# OpenTallas memory compiler (tools/mem_compiler), ASAP7 abstract view
VERSION 5.7 ;
BUSBITCHARS "[]" ;
DIVIDERCHAR "/" ;
PROPERTYDEFINITIONS
  MACRO width INTEGER ;
  MACRO depth INTEGER ;
  MACRO banks INTEGER ;
END PROPERTYDEFINITIONS
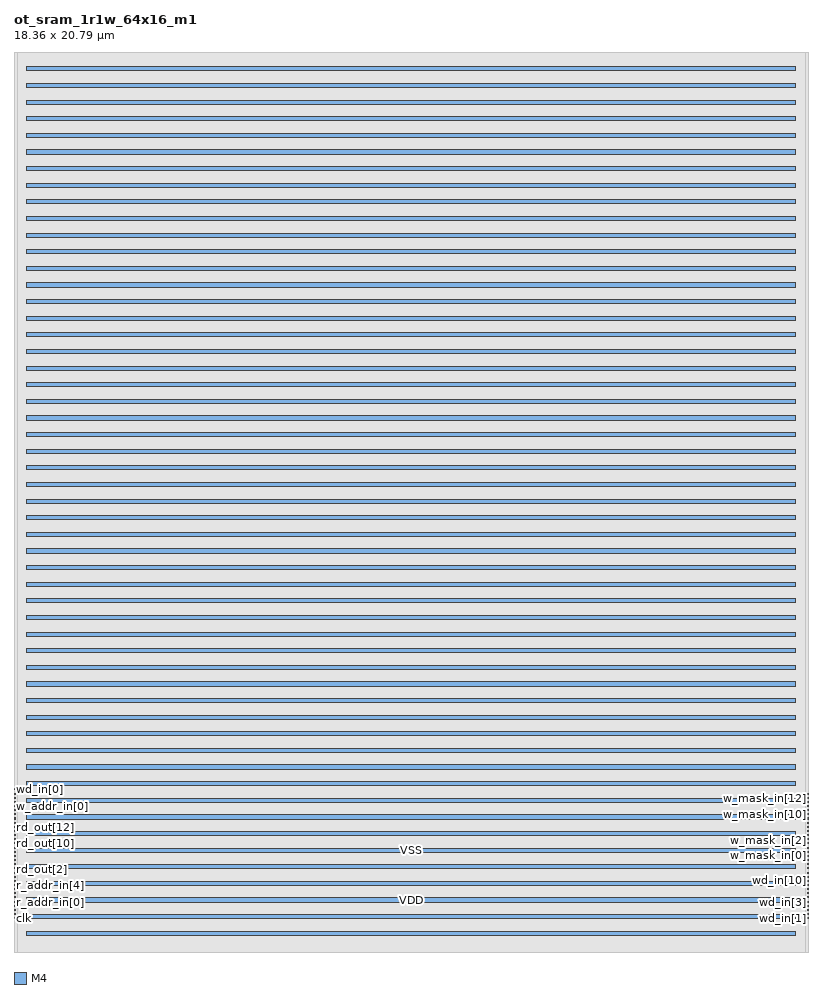
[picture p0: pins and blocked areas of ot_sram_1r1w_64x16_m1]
MACRO ot_sram_1r1w_64x16_m1
  PROPERTY width 16 ;
  PROPERTY depth 64 ;
  PROPERTY banks 1 ;
  FOREIGN ot_sram_1r1w_64x16_m1 0 0 ;
  SYMMETRY X Y R90 ;
  SIZE 18.360 BY 20.790 ;
  CLASS BLOCK ;
  PIN clk
    DIRECTION INPUT ;
    USE CLOCK ;
    SHAPE ABUTMENT ;
    PORT
      LAYER M4 ;
      RECT 0.000 0.768 0.024 0.792 ;
    END
  END clk
  PIN r_ce_in
    DIRECTION INPUT ;
    USE SIGNAL ;
    SHAPE ABUTMENT ;
    PORT
      LAYER M4 ;
      RECT 0.000 0.864 0.024 0.888 ;
    END
  END r_ce_in
  PIN r_addr_in[0]
    DIRECTION INPUT ;
    USE SIGNAL ;
    SHAPE ABUTMENT ;
    PORT
      LAYER M4 ;
      RECT 0.000 0.960 0.024 0.984 ;
    END
  END r_addr_in[0]
  PIN r_addr_in[1]
    DIRECTION INPUT ;
    USE SIGNAL ;
    SHAPE ABUTMENT ;
    PORT
      LAYER M4 ;
      RECT 0.000 1.056 0.024 1.080 ;
    END
  END r_addr_in[1]
  PIN r_addr_in[2]
    DIRECTION INPUT ;
    USE SIGNAL ;
    SHAPE ABUTMENT ;
    PORT
      LAYER M4 ;
      RECT 0.000 1.152 0.024 1.176 ;
    END
  END r_addr_in[2]
  PIN r_addr_in[3]
    DIRECTION INPUT ;
    USE SIGNAL ;
    SHAPE ABUTMENT ;
    PORT
      LAYER M4 ;
      RECT 0.000 1.248 0.024 1.272 ;
    END
  END r_addr_in[3]
  PIN r_addr_in[4]
    DIRECTION INPUT ;
    USE SIGNAL ;
    SHAPE ABUTMENT ;
    PORT
      LAYER M4 ;
      RECT 0.000 1.344 0.024 1.368 ;
    END
  END r_addr_in[4]
  PIN r_addr_in[5]
    DIRECTION INPUT ;
    USE SIGNAL ;
    SHAPE ABUTMENT ;
    PORT
      LAYER M4 ;
      RECT 0.000 1.440 0.024 1.464 ;
    END
  END r_addr_in[5]
  PIN rd_out[0]
    DIRECTION OUTPUT ;
    USE SIGNAL ;
    SHAPE ABUTMENT ;
    PORT
      LAYER M4 ;
      RECT 0.000 1.536 0.024 1.560 ;
    END
  END rd_out[0]
  PIN rd_out[1]
    DIRECTION OUTPUT ;
    USE SIGNAL ;
    SHAPE ABUTMENT ;
    PORT
      LAYER M4 ;
      RECT 0.000 1.632 0.024 1.656 ;
    END
  END rd_out[1]
  PIN rd_out[2]
    DIRECTION OUTPUT ;
    USE SIGNAL ;
    SHAPE ABUTMENT ;
    PORT
      LAYER M4 ;
      RECT 0.000 1.728 0.024 1.752 ;
    END
  END rd_out[2]
  PIN rd_out[3]
    DIRECTION OUTPUT ;
    USE SIGNAL ;
    SHAPE ABUTMENT ;
    PORT
      LAYER M4 ;
      RECT 0.000 1.824 0.024 1.848 ;
    END
  END rd_out[3]
  PIN rd_out[4]
    DIRECTION OUTPUT ;
    USE SIGNAL ;
    SHAPE ABUTMENT ;
    PORT
      LAYER M4 ;
      RECT 0.000 1.920 0.024 1.944 ;
    END
  END rd_out[4]
  PIN rd_out[5]
    DIRECTION OUTPUT ;
    USE SIGNAL ;
    SHAPE ABUTMENT ;
    PORT
      LAYER M4 ;
      RECT 0.000 2.016 0.024 2.040 ;
    END
  END rd_out[5]
  PIN rd_out[6]
    DIRECTION OUTPUT ;
    USE SIGNAL ;
    SHAPE ABUTMENT ;
    PORT
      LAYER M4 ;
      RECT 0.000 2.112 0.024 2.136 ;
    END
  END rd_out[6]
  PIN rd_out[7]
    DIRECTION OUTPUT ;
    USE SIGNAL ;
    SHAPE ABUTMENT ;
    PORT
      LAYER M4 ;
      RECT 0.000 2.208 0.024 2.232 ;
    END
  END rd_out[7]
  PIN rd_out[8]
    DIRECTION OUTPUT ;
    USE SIGNAL ;
    SHAPE ABUTMENT ;
    PORT
      LAYER M4 ;
      RECT 0.000 2.304 0.024 2.328 ;
    END
  END rd_out[8]
  PIN rd_out[9]
    DIRECTION OUTPUT ;
    USE SIGNAL ;
    SHAPE ABUTMENT ;
    PORT
      LAYER M4 ;
      RECT 0.000 2.400 0.024 2.424 ;
    END
  END rd_out[9]
  PIN rd_out[10]
    DIRECTION OUTPUT ;
    USE SIGNAL ;
    SHAPE ABUTMENT ;
    PORT
      LAYER M4 ;
      RECT 0.000 2.496 0.024 2.520 ;
    END
  END rd_out[10]
  PIN rd_out[11]
    DIRECTION OUTPUT ;
    USE SIGNAL ;
    SHAPE ABUTMENT ;
    PORT
      LAYER M4 ;
      RECT 0.000 2.592 0.024 2.616 ;
    END
  END rd_out[11]
  PIN rd_out[12]
    DIRECTION OUTPUT ;
    USE SIGNAL ;
    SHAPE ABUTMENT ;
    PORT
      LAYER M4 ;
      RECT 0.000 2.688 0.024 2.712 ;
    END
  END rd_out[12]
  PIN rd_out[13]
    DIRECTION OUTPUT ;
    USE SIGNAL ;
    SHAPE ABUTMENT ;
    PORT
      LAYER M4 ;
      RECT 0.000 2.784 0.024 2.808 ;
    END
  END rd_out[13]
  PIN rd_out[14]
    DIRECTION OUTPUT ;
    USE SIGNAL ;
    SHAPE ABUTMENT ;
    PORT
      LAYER M4 ;
      RECT 0.000 2.880 0.024 2.904 ;
    END
  END rd_out[14]
  PIN rd_out[15]
    DIRECTION OUTPUT ;
    USE SIGNAL ;
    SHAPE ABUTMENT ;
    PORT
      LAYER M4 ;
      RECT 0.000 2.976 0.024 3.000 ;
    END
  END rd_out[15]
  PIN w_ce_in
    DIRECTION INPUT ;
    USE SIGNAL ;
    SHAPE ABUTMENT ;
    PORT
      LAYER M4 ;
      RECT 0.000 3.072 0.024 3.096 ;
    END
  END w_ce_in
  PIN w_addr_in[0]
    DIRECTION INPUT ;
    USE SIGNAL ;
    SHAPE ABUTMENT ;
    PORT
      LAYER M4 ;
      RECT 0.000 3.168 0.024 3.192 ;
    END
  END w_addr_in[0]
  PIN w_addr_in[1]
    DIRECTION INPUT ;
    USE SIGNAL ;
    SHAPE ABUTMENT ;
    PORT
      LAYER M4 ;
      RECT 0.000 3.264 0.024 3.288 ;
    END
  END w_addr_in[1]
  PIN w_addr_in[2]
    DIRECTION INPUT ;
    USE SIGNAL ;
    SHAPE ABUTMENT ;
    PORT
      LAYER M4 ;
      RECT 0.000 3.360 0.024 3.384 ;
    END
  END w_addr_in[2]
  PIN w_addr_in[3]
    DIRECTION INPUT ;
    USE SIGNAL ;
    SHAPE ABUTMENT ;
    PORT
      LAYER M4 ;
      RECT 0.000 3.456 0.024 3.480 ;
    END
  END w_addr_in[3]
  PIN w_addr_in[4]
    DIRECTION INPUT ;
    USE SIGNAL ;
    SHAPE ABUTMENT ;
    PORT
      LAYER M4 ;
      RECT 0.000 3.552 0.024 3.576 ;
    END
  END w_addr_in[4]
  PIN w_addr_in[5]
    DIRECTION INPUT ;
    USE SIGNAL ;
    SHAPE ABUTMENT ;
    PORT
      LAYER M4 ;
      RECT 0.000 3.648 0.024 3.672 ;
    END
  END w_addr_in[5]
  PIN wd_in[0]
    DIRECTION INPUT ;
    USE SIGNAL ;
    SHAPE ABUTMENT ;
    PORT
      LAYER M4 ;
      RECT 0.000 3.744 0.024 3.768 ;
    END
  END wd_in[0]
  PIN wd_in[1]
    DIRECTION INPUT ;
    USE SIGNAL ;
    SHAPE ABUTMENT ;
    PORT
      LAYER M4 ;
      RECT 18.336 0.768 18.360 0.792 ;
    END
  END wd_in[1]
  PIN wd_in[2]
    DIRECTION INPUT ;
    USE SIGNAL ;
    SHAPE ABUTMENT ;
    PORT
      LAYER M4 ;
      RECT 18.336 0.864 18.360 0.888 ;
    END
  END wd_in[2]
  PIN wd_in[3]
    DIRECTION INPUT ;
    USE SIGNAL ;
    SHAPE ABUTMENT ;
    PORT
      LAYER M4 ;
      RECT 18.336 0.960 18.360 0.984 ;
    END
  END wd_in[3]
  PIN wd_in[4]
    DIRECTION INPUT ;
    USE SIGNAL ;
    SHAPE ABUTMENT ;
    PORT
      LAYER M4 ;
      RECT 18.336 1.056 18.360 1.080 ;
    END
  END wd_in[4]
  PIN wd_in[5]
    DIRECTION INPUT ;
    USE SIGNAL ;
    SHAPE ABUTMENT ;
    PORT
      LAYER M4 ;
      RECT 18.336 1.152 18.360 1.176 ;
    END
  END wd_in[5]
  PIN wd_in[6]
    DIRECTION INPUT ;
    USE SIGNAL ;
    SHAPE ABUTMENT ;
    PORT
      LAYER M4 ;
      RECT 18.336 1.248 18.360 1.272 ;
    END
  END wd_in[6]
  PIN wd_in[7]
    DIRECTION INPUT ;
    USE SIGNAL ;
    SHAPE ABUTMENT ;
    PORT
      LAYER M4 ;
      RECT 18.336 1.344 18.360 1.368 ;
    END
  END wd_in[7]
  PIN wd_in[8]
    DIRECTION INPUT ;
    USE SIGNAL ;
    SHAPE ABUTMENT ;
    PORT
      LAYER M4 ;
      RECT 18.336 1.440 18.360 1.464 ;
    END
  END wd_in[8]
  PIN wd_in[9]
    DIRECTION INPUT ;
    USE SIGNAL ;
    SHAPE ABUTMENT ;
    PORT
      LAYER M4 ;
      RECT 18.336 1.536 18.360 1.560 ;
    END
  END wd_in[9]
  PIN wd_in[10]
    DIRECTION INPUT ;
    USE SIGNAL ;
    SHAPE ABUTMENT ;
    PORT
      LAYER M4 ;
      RECT 18.336 1.632 18.360 1.656 ;
    END
  END wd_in[10]
  PIN wd_in[11]
    DIRECTION INPUT ;
    USE SIGNAL ;
    SHAPE ABUTMENT ;
    PORT
      LAYER M4 ;
      RECT 18.336 1.728 18.360 1.752 ;
    END
  END wd_in[11]
  PIN wd_in[12]
    DIRECTION INPUT ;
    USE SIGNAL ;
    SHAPE ABUTMENT ;
    PORT
      LAYER M4 ;
      RECT 18.336 1.824 18.360 1.848 ;
    END
  END wd_in[12]
  PIN wd_in[13]
    DIRECTION INPUT ;
    USE SIGNAL ;
    SHAPE ABUTMENT ;
    PORT
      LAYER M4 ;
      RECT 18.336 1.920 18.360 1.944 ;
    END
  END wd_in[13]
  PIN wd_in[14]
    DIRECTION INPUT ;
    USE SIGNAL ;
    SHAPE ABUTMENT ;
    PORT
      LAYER M4 ;
      RECT 18.336 2.016 18.360 2.040 ;
    END
  END wd_in[14]
  PIN wd_in[15]
    DIRECTION INPUT ;
    USE SIGNAL ;
    SHAPE ABUTMENT ;
    PORT
      LAYER M4 ;
      RECT 18.336 2.112 18.360 2.136 ;
    END
  END wd_in[15]
  PIN w_mask_in[0]
    DIRECTION INPUT ;
    USE SIGNAL ;
    SHAPE ABUTMENT ;
    PORT
      LAYER M4 ;
      RECT 18.336 2.208 18.360 2.232 ;
    END
  END w_mask_in[0]
  PIN w_mask_in[1]
    DIRECTION INPUT ;
    USE SIGNAL ;
    SHAPE ABUTMENT ;
    PORT
      LAYER M4 ;
      RECT 18.336 2.304 18.360 2.328 ;
    END
  END w_mask_in[1]
  PIN w_mask_in[2]
    DIRECTION INPUT ;
    USE SIGNAL ;
    SHAPE ABUTMENT ;
    PORT
      LAYER M4 ;
      RECT 18.336 2.400 18.360 2.424 ;
    END
  END w_mask_in[2]
  PIN w_mask_in[3]
    DIRECTION INPUT ;
    USE SIGNAL ;
    SHAPE ABUTMENT ;
    PORT
      LAYER M4 ;
      RECT 18.336 2.496 18.360 2.520 ;
    END
  END w_mask_in[3]
  PIN w_mask_in[4]
    DIRECTION INPUT ;
    USE SIGNAL ;
    SHAPE ABUTMENT ;
    PORT
      LAYER M4 ;
      RECT 18.336 2.592 18.360 2.616 ;
    END
  END w_mask_in[4]
  PIN w_mask_in[5]
    DIRECTION INPUT ;
    USE SIGNAL ;
    SHAPE ABUTMENT ;
    PORT
      LAYER M4 ;
      RECT 18.336 2.688 18.360 2.712 ;
    END
  END w_mask_in[5]
  PIN w_mask_in[6]
    DIRECTION INPUT ;
    USE SIGNAL ;
    SHAPE ABUTMENT ;
    PORT
      LAYER M4 ;
      RECT 18.336 2.784 18.360 2.808 ;
    END
  END w_mask_in[6]
  PIN w_mask_in[7]
    DIRECTION INPUT ;
    USE SIGNAL ;
    SHAPE ABUTMENT ;
    PORT
      LAYER M4 ;
      RECT 18.336 2.880 18.360 2.904 ;
    END
  END w_mask_in[7]
  PIN w_mask_in[8]
    DIRECTION INPUT ;
    USE SIGNAL ;
    SHAPE ABUTMENT ;
    PORT
      LAYER M4 ;
      RECT 18.336 2.976 18.360 3.000 ;
    END
  END w_mask_in[8]
  PIN w_mask_in[9]
    DIRECTION INPUT ;
    USE SIGNAL ;
    SHAPE ABUTMENT ;
    PORT
      LAYER M4 ;
      RECT 18.336 3.072 18.360 3.096 ;
    END
  END w_mask_in[9]
  PIN w_mask_in[10]
    DIRECTION INPUT ;
    USE SIGNAL ;
    SHAPE ABUTMENT ;
    PORT
      LAYER M4 ;
      RECT 18.336 3.168 18.360 3.192 ;
    END
  END w_mask_in[10]
  PIN w_mask_in[11]
    DIRECTION INPUT ;
    USE SIGNAL ;
    SHAPE ABUTMENT ;
    PORT
      LAYER M4 ;
      RECT 18.336 3.264 18.360 3.288 ;
    END
  END w_mask_in[11]
  PIN w_mask_in[12]
    DIRECTION INPUT ;
    USE SIGNAL ;
    SHAPE ABUTMENT ;
    PORT
      LAYER M4 ;
      RECT 18.336 3.360 18.360 3.384 ;
    END
  END w_mask_in[12]
  PIN w_mask_in[13]
    DIRECTION INPUT ;
    USE SIGNAL ;
    SHAPE ABUTMENT ;
    PORT
      LAYER M4 ;
      RECT 18.336 3.456 18.360 3.480 ;
    END
  END w_mask_in[13]
  PIN w_mask_in[14]
    DIRECTION INPUT ;
    USE SIGNAL ;
    SHAPE ABUTMENT ;
    PORT
      LAYER M4 ;
      RECT 18.336 3.552 18.360 3.576 ;
    END
  END w_mask_in[14]
  PIN w_mask_in[15]
    DIRECTION INPUT ;
    USE SIGNAL ;
    SHAPE ABUTMENT ;
    PORT
      LAYER M4 ;
      RECT 18.336 3.648 18.360 3.672 ;
    END
  END w_mask_in[15]
  PIN VDD
    DIRECTION INOUT ;
    USE POWER ;
    PORT
      LAYER M4 ;
      RECT 0.300 0.384 18.060 0.480 ;
      RECT 0.300 1.152 18.060 1.248 ;
      RECT 0.300 1.920 18.060 2.016 ;
      RECT 0.300 2.688 18.060 2.784 ;
      RECT 0.300 3.456 18.060 3.552 ;
      RECT 0.300 4.224 18.060 4.320 ;
      RECT 0.300 4.992 18.060 5.088 ;
      RECT 0.300 5.760 18.060 5.856 ;
      RECT 0.300 6.528 18.060 6.624 ;
      RECT 0.300 7.296 18.060 7.392 ;
      RECT 0.300 8.064 18.060 8.160 ;
      RECT 0.300 8.832 18.060 8.928 ;
      RECT 0.300 9.600 18.060 9.696 ;
      RECT 0.300 10.368 18.060 10.464 ;
      RECT 0.300 11.136 18.060 11.232 ;
      RECT 0.300 11.904 18.060 12.000 ;
      RECT 0.300 12.672 18.060 12.768 ;
      RECT 0.300 13.440 18.060 13.536 ;
      RECT 0.300 14.208 18.060 14.304 ;
      RECT 0.300 14.976 18.060 15.072 ;
      RECT 0.300 15.744 18.060 15.840 ;
      RECT 0.300 16.512 18.060 16.608 ;
      RECT 0.300 17.280 18.060 17.376 ;
      RECT 0.300 18.048 18.060 18.144 ;
      RECT 0.300 18.816 18.060 18.912 ;
      RECT 0.300 19.584 18.060 19.680 ;
      RECT 0.300 20.352 18.060 20.448 ;
    END
  END VDD
  PIN VSS
    DIRECTION INOUT ;
    USE GROUND ;
    PORT
      LAYER M4 ;
      RECT 0.300 0.768 18.060 0.864 ;
      RECT 0.300 1.536 18.060 1.632 ;
      RECT 0.300 2.304 18.060 2.400 ;
      RECT 0.300 3.072 18.060 3.168 ;
      RECT 0.300 3.840 18.060 3.936 ;
      RECT 0.300 4.608 18.060 4.704 ;
      RECT 0.300 5.376 18.060 5.472 ;
      RECT 0.300 6.144 18.060 6.240 ;
      RECT 0.300 6.912 18.060 7.008 ;
      RECT 0.300 7.680 18.060 7.776 ;
      RECT 0.300 8.448 18.060 8.544 ;
      RECT 0.300 9.216 18.060 9.312 ;
      RECT 0.300 9.984 18.060 10.080 ;
      RECT 0.300 10.752 18.060 10.848 ;
      RECT 0.300 11.520 18.060 11.616 ;
      RECT 0.300 12.288 18.060 12.384 ;
      RECT 0.300 13.056 18.060 13.152 ;
      RECT 0.300 13.824 18.060 13.920 ;
      RECT 0.300 14.592 18.060 14.688 ;
      RECT 0.300 15.360 18.060 15.456 ;
      RECT 0.300 16.128 18.060 16.224 ;
      RECT 0.300 16.896 18.060 16.992 ;
      RECT 0.300 17.664 18.060 17.760 ;
      RECT 0.300 18.432 18.060 18.528 ;
      RECT 0.300 19.200 18.060 19.296 ;
      RECT 0.300 19.968 18.060 20.064 ;
    END
  END VSS
  OBS
    LAYER M1 ;
    RECT 0 0 18.360 20.790 ;
    LAYER M2 ;
    RECT 0 0 18.360 20.790 ;
    LAYER M3 ;
    RECT 0 0 18.360 20.790 ;
    LAYER M4 ;
    RECT 0.072 0 18.288 20.790 ;
  END
END ot_sram_1r1w_64x16_m1

END LIBRARY
